VERSION 5.7 ;
  NOWIREEXTENSIONATPIN ON ;
  DIVIDERCHAR "/" ;
  BUSBITCHARS "[]" ;
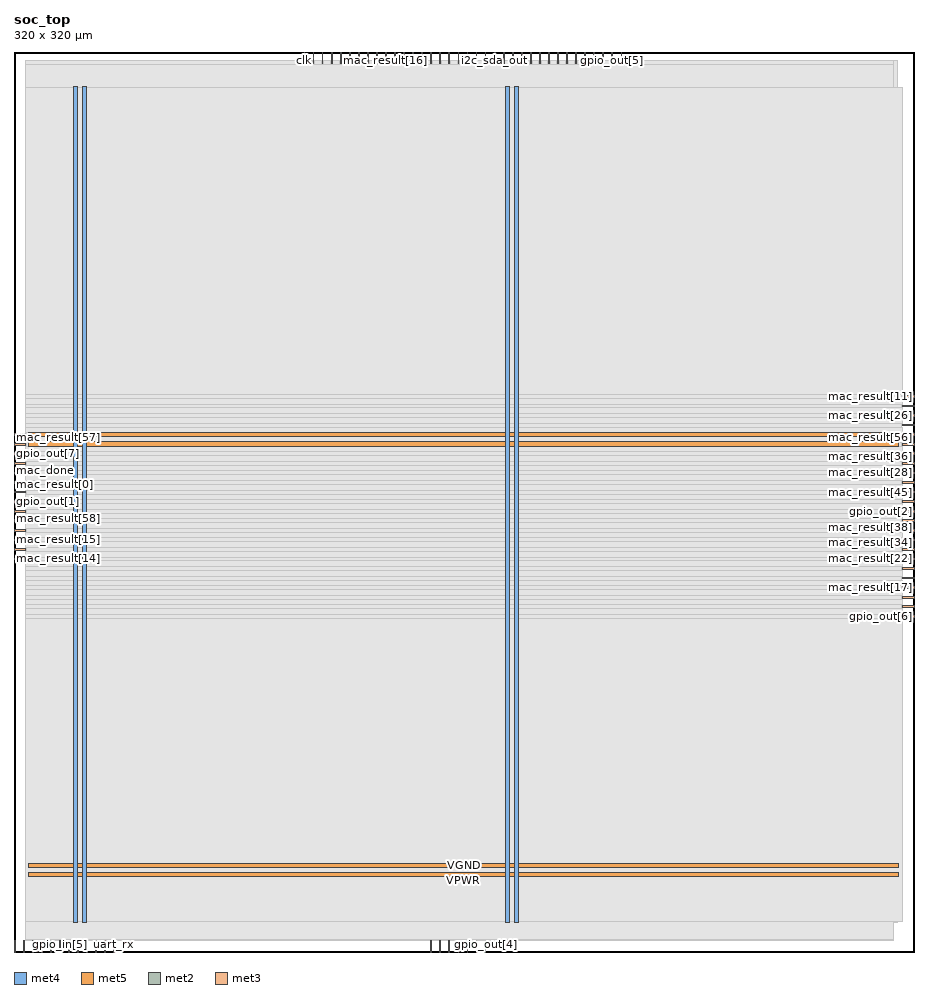
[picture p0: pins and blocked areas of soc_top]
MACRO soc_top
  CLASS BLOCK ;
  FOREIGN soc_top ;
  ORIGIN 0.000 0.000 ;
  SIZE 320.000 BY 320.000 ;
  PIN VGND
    DIRECTION INOUT ;
    USE GROUND ;
    PORT
      LAYER met4 ;
        RECT 24.340 10.640 25.940 307.600 ;
    END
    PORT
      LAYER met4 ;
        RECT 177.940 10.640 179.540 307.600 ;
    END
    PORT
      LAYER met5 ;
        RECT 5.280 30.030 314.420 31.630 ;
    END
    PORT
      LAYER met5 ;
        RECT 5.280 183.210 314.420 184.810 ;
    END
  END VGND
  PIN VPWR
    DIRECTION INOUT ;
    USE POWER ;
    PORT
      LAYER met4 ;
        RECT 21.040 10.640 22.640 307.600 ;
    END
    PORT
      LAYER met4 ;
        RECT 174.640 10.640 176.240 307.600 ;
    END
    PORT
      LAYER met5 ;
        RECT 5.280 26.730 314.420 28.330 ;
    END
    PORT
      LAYER met5 ;
        RECT 5.280 179.910 314.420 181.510 ;
    END
  END VPWR
  PIN clk
    DIRECTION INPUT ;
    USE SIGNAL ;
    ANTENNAGATEAREA 0.852000 ;
    PORT
      LAYER met2 ;
        RECT 103.130 316.000 103.410 320.000 ;
    END
  END clk
  PIN gpio_in[0]
    DIRECTION INPUT ;
    USE SIGNAL ;
    PORT
      LAYER met2 ;
        RECT 0.090 0.000 0.370 4.000 ;
    END
  END gpio_in[0]
  PIN gpio_in[1]
    DIRECTION INPUT ;
    USE SIGNAL ;
    PORT
      LAYER met2 ;
        RECT 3.310 0.000 3.590 4.000 ;
    END
  END gpio_in[1]
  PIN gpio_in[2]
    DIRECTION INPUT ;
    USE SIGNAL ;
    PORT
      LAYER met2 ;
        RECT 6.530 0.000 6.810 4.000 ;
    END
  END gpio_in[2]
  PIN gpio_in[3]
    DIRECTION INPUT ;
    USE SIGNAL ;
    PORT
      LAYER met2 ;
        RECT 9.750 0.000 10.030 4.000 ;
    END
  END gpio_in[3]
  PIN gpio_in[4]
    DIRECTION INPUT ;
    USE SIGNAL ;
    PORT
      LAYER met2 ;
        RECT 12.970 0.000 13.250 4.000 ;
    END
  END gpio_in[4]
  PIN gpio_in[5]
    DIRECTION INPUT ;
    USE SIGNAL ;
    PORT
      LAYER met2 ;
        RECT 16.190 0.000 16.470 4.000 ;
    END
  END gpio_in[5]
  PIN gpio_in[6]
    DIRECTION INPUT ;
    USE SIGNAL ;
    PORT
      LAYER met2 ;
        RECT 19.410 0.000 19.690 4.000 ;
    END
  END gpio_in[6]
  PIN gpio_in[7]
    DIRECTION INPUT ;
    USE SIGNAL ;
    PORT
      LAYER met2 ;
        RECT 22.630 0.000 22.910 4.000 ;
    END
  END gpio_in[7]
  PIN gpio_out[0]
    DIRECTION OUTPUT ;
    USE SIGNAL ;
    PORT
      LAYER met3 ;
        RECT 0.000 183.640 4.000 184.240 ;
    END
  END gpio_out[0]
  PIN gpio_out[1]
    DIRECTION OUTPUT ;
    USE SIGNAL ;
    PORT
      LAYER met3 ;
        RECT 0.000 159.840 4.000 160.440 ;
    END
  END gpio_out[1]
  PIN gpio_out[2]
    DIRECTION OUTPUT ;
    USE SIGNAL ;
    PORT
      LAYER met3 ;
        RECT 316.000 156.440 320.000 157.040 ;
    END
  END gpio_out[2]
  PIN gpio_out[3]
    DIRECTION OUTPUT ;
    USE SIGNAL ;
    PORT
      LAYER met2 ;
        RECT 112.790 316.000 113.070 320.000 ;
    END
  END gpio_out[3]
  PIN gpio_out[4]
    DIRECTION OUTPUT ;
    USE SIGNAL ;
    PORT
      LAYER met2 ;
        RECT 167.530 0.000 167.810 4.000 ;
    END
  END gpio_out[4]
  PIN gpio_out[5]
    DIRECTION OUTPUT ;
    USE SIGNAL ;
    PORT
      LAYER met2 ;
        RECT 212.610 316.000 212.890 320.000 ;
    END
  END gpio_out[5]
  PIN gpio_out[6]
    DIRECTION OUTPUT ;
    USE SIGNAL ;
    PORT
      LAYER met3 ;
        RECT 316.000 119.040 320.000 119.640 ;
    END
  END gpio_out[6]
  PIN gpio_out[7]
    DIRECTION OUTPUT ;
    USE SIGNAL ;
    PORT
      LAYER met3 ;
        RECT 0.000 176.840 4.000 177.440 ;
    END
  END gpio_out[7]
  PIN i2c_scl
    DIRECTION OUTPUT ;
    USE SIGNAL ;
    ANTENNADIFFAREA 0.340600 ;
    PORT
      LAYER met2 ;
        RECT 151.430 316.000 151.710 320.000 ;
    END
  END i2c_scl
  PIN i2c_sda_in
    DIRECTION INPUT ;
    USE SIGNAL ;
    PORT
      LAYER met2 ;
        RECT 25.850 0.000 26.130 4.000 ;
    END
  END i2c_sda_in
  PIN i2c_sda_out
    DIRECTION OUTPUT ;
    USE SIGNAL ;
    PORT
      LAYER met2 ;
        RECT 170.750 316.000 171.030 320.000 ;
    END
  END i2c_sda_out
  PIN mac_done
    DIRECTION OUTPUT ;
    USE SIGNAL ;
    PORT
      LAYER met3 ;
        RECT 0.000 173.440 4.000 174.040 ;
    END
  END mac_done
  PIN mac_result[0]
    DIRECTION OUTPUT ;
    USE SIGNAL ;
    PORT
      LAYER met3 ;
        RECT 0.000 163.240 4.000 163.840 ;
    END
  END mac_result[0]
  PIN mac_result[10]
    DIRECTION OUTPUT ;
    USE SIGNAL ;
    PORT
      LAYER met3 ;
        RECT 316.000 122.440 320.000 123.040 ;
    END
  END mac_result[10]
  PIN mac_result[11]
    DIRECTION OUTPUT ;
    USE SIGNAL ;
    PORT
      LAYER met3 ;
        RECT 316.000 197.240 320.000 197.840 ;
    END
  END mac_result[11]
  PIN mac_result[12]
    DIRECTION OUTPUT ;
    USE SIGNAL ;
    PORT
      LAYER met2 ;
        RECT 177.190 316.000 177.470 320.000 ;
    END
  END mac_result[12]
  PIN mac_result[13]
    DIRECTION OUTPUT ;
    USE SIGNAL ;
    PORT
      LAYER met3 ;
        RECT 316.000 166.640 320.000 167.240 ;
    END
  END mac_result[13]
  PIN mac_result[14]
    DIRECTION OUTPUT ;
    USE SIGNAL ;
    PORT
      LAYER met3 ;
        RECT 0.000 139.440 4.000 140.040 ;
    END
  END mac_result[14]
  PIN mac_result[15]
    DIRECTION OUTPUT ;
    USE SIGNAL ;
    PORT
      LAYER met3 ;
        RECT 0.000 146.240 4.000 146.840 ;
    END
  END mac_result[15]
  PIN mac_result[16]
    DIRECTION OUTPUT ;
    USE SIGNAL ;
    PORT
      LAYER met2 ;
        RECT 132.110 316.000 132.390 320.000 ;
    END
  END mac_result[16]
  PIN mac_result[17]
    DIRECTION OUTPUT ;
    USE SIGNAL ;
    PORT
      LAYER met3 ;
        RECT 316.000 129.240 320.000 129.840 ;
    END
  END mac_result[17]
  PIN mac_result[18]
    DIRECTION OUTPUT ;
    USE SIGNAL ;
    PORT
      LAYER met3 ;
        RECT 0.000 166.640 4.000 167.240 ;
    END
  END mac_result[18]
  PIN mac_result[19]
    DIRECTION OUTPUT ;
    USE SIGNAL ;
    PORT
      LAYER met2 ;
        RECT 164.310 316.000 164.590 320.000 ;
    END
  END mac_result[19]
  PIN mac_result[1]
    DIRECTION OUTPUT ;
    USE SIGNAL ;
    PORT
      LAYER met2 ;
        RECT 154.650 316.000 154.930 320.000 ;
    END
  END mac_result[1]
  PIN mac_result[20]
    DIRECTION OUTPUT ;
    USE SIGNAL ;
    PORT
      LAYER met2 ;
        RECT 122.450 316.000 122.730 320.000 ;
    END
  END mac_result[20]
  PIN mac_result[21]
    DIRECTION OUTPUT ;
    USE SIGNAL ;
    PORT
      LAYER met3 ;
        RECT 0.000 170.040 4.000 170.640 ;
    END
  END mac_result[21]
  PIN mac_result[22]
    DIRECTION OUTPUT ;
    USE SIGNAL ;
    PORT
      LAYER met3 ;
        RECT 316.000 139.440 320.000 140.040 ;
    END
  END mac_result[22]
  PIN mac_result[23]
    DIRECTION OUTPUT ;
    USE SIGNAL ;
    PORT
      LAYER met2 ;
        RECT 125.670 316.000 125.950 320.000 ;
    END
  END mac_result[23]
  PIN mac_result[24]
    DIRECTION OUTPUT ;
    USE SIGNAL ;
    PORT
      LAYER met2 ;
        RECT 167.530 316.000 167.810 320.000 ;
    END
  END mac_result[24]
  PIN mac_result[25]
    DIRECTION OUTPUT ;
    USE SIGNAL ;
    PORT
      LAYER met2 ;
        RECT 190.070 316.000 190.350 320.000 ;
    END
  END mac_result[25]
  PIN mac_result[26]
    DIRECTION OUTPUT ;
    USE SIGNAL ;
    PORT
      LAYER met3 ;
        RECT 316.000 190.440 320.000 191.040 ;
    END
  END mac_result[26]
  PIN mac_result[27]
    DIRECTION OUTPUT ;
    USE SIGNAL ;
    PORT
      LAYER met2 ;
        RECT 202.950 316.000 203.230 320.000 ;
    END
  END mac_result[27]
  PIN mac_result[28]
    DIRECTION OUTPUT ;
    USE SIGNAL ;
    PORT
      LAYER met3 ;
        RECT 316.000 170.040 320.000 170.640 ;
    END
  END mac_result[28]
  PIN mac_result[29]
    DIRECTION OUTPUT ;
    USE SIGNAL ;
    PORT
      LAYER met2 ;
        RECT 128.890 316.000 129.170 320.000 ;
    END
  END mac_result[29]
  PIN mac_result[2]
    DIRECTION OUTPUT ;
    USE SIGNAL ;
    PORT
      LAYER met2 ;
        RECT 161.090 316.000 161.370 320.000 ;
    END
  END mac_result[2]
  PIN mac_result[30]
    DIRECTION OUTPUT ;
    USE SIGNAL ;
    PORT
      LAYER met2 ;
        RECT 116.010 316.000 116.290 320.000 ;
    END
  END mac_result[30]
  PIN mac_result[31]
    DIRECTION OUTPUT ;
    USE SIGNAL ;
    PORT
      LAYER met3 ;
        RECT 316.000 136.040 320.000 136.640 ;
    END
  END mac_result[31]
  PIN mac_result[32]
    DIRECTION OUTPUT ;
    USE SIGNAL ;
    PORT
      LAYER met2 ;
        RECT 161.090 0.000 161.370 4.000 ;
    END
  END mac_result[32]
  PIN mac_result[33]
    DIRECTION OUTPUT ;
    USE SIGNAL ;
    PORT
      LAYER met2 ;
        RECT 138.550 316.000 138.830 320.000 ;
    END
  END mac_result[33]
  PIN mac_result[34]
    DIRECTION OUTPUT ;
    USE SIGNAL ;
    PORT
      LAYER met3 ;
        RECT 316.000 142.840 320.000 143.440 ;
    END
  END mac_result[34]
  PIN mac_result[35]
    DIRECTION OUTPUT ;
    USE SIGNAL ;
    PORT
      LAYER met2 ;
        RECT 148.210 0.000 148.490 4.000 ;
    END
  END mac_result[35]
  PIN mac_result[36]
    DIRECTION OUTPUT ;
    USE SIGNAL ;
    PORT
      LAYER met3 ;
        RECT 316.000 173.440 320.000 174.040 ;
    END
  END mac_result[36]
  PIN mac_result[37]
    DIRECTION OUTPUT ;
    USE SIGNAL ;
    PORT
      LAYER met2 ;
        RECT 196.510 316.000 196.790 320.000 ;
    END
  END mac_result[37]
  PIN mac_result[38]
    DIRECTION OUTPUT ;
    USE SIGNAL ;
    PORT
      LAYER met3 ;
        RECT 316.000 153.040 320.000 153.640 ;
    END
  END mac_result[38]
  PIN mac_result[39]
    DIRECTION OUTPUT ;
    USE SIGNAL ;
    PORT
      LAYER met3 ;
        RECT 316.000 183.640 320.000 184.240 ;
    END
  END mac_result[39]
  PIN mac_result[3]
    DIRECTION OUTPUT ;
    USE SIGNAL ;
    PORT
      LAYER met2 ;
        RECT 215.830 316.000 216.110 320.000 ;
    END
  END mac_result[3]
  PIN mac_result[40]
    DIRECTION OUTPUT ;
    USE SIGNAL ;
    PORT
      LAYER met2 ;
        RECT 180.410 316.000 180.690 320.000 ;
    END
  END mac_result[40]
  PIN mac_result[41]
    DIRECTION OUTPUT ;
    USE SIGNAL ;
    PORT
      LAYER met2 ;
        RECT 193.290 316.000 193.570 320.000 ;
    END
  END mac_result[41]
  PIN mac_result[42]
    DIRECTION OUTPUT ;
    USE SIGNAL ;
    PORT
      LAYER met2 ;
        RECT 209.390 316.000 209.670 320.000 ;
    END
  END mac_result[42]
  PIN mac_result[43]
    DIRECTION OUTPUT ;
    USE SIGNAL ;
    PORT
      LAYER met3 ;
        RECT 316.000 132.640 320.000 133.240 ;
    END
  END mac_result[43]
  PIN mac_result[44]
    DIRECTION OUTPUT ;
    USE SIGNAL ;
    PORT
      LAYER met3 ;
        RECT 316.000 176.840 320.000 177.440 ;
    END
  END mac_result[44]
  PIN mac_result[45]
    DIRECTION OUTPUT ;
    USE SIGNAL ;
    PORT
      LAYER met3 ;
        RECT 316.000 163.240 320.000 163.840 ;
    END
  END mac_result[45]
  PIN mac_result[46]
    DIRECTION OUTPUT ;
    USE SIGNAL ;
    PORT
      LAYER met3 ;
        RECT 0.000 149.640 4.000 150.240 ;
    END
  END mac_result[46]
  PIN mac_result[47]
    DIRECTION OUTPUT ;
    USE SIGNAL ;
    PORT
      LAYER met2 ;
        RECT 206.170 316.000 206.450 320.000 ;
    END
  END mac_result[47]
  PIN mac_result[48]
    DIRECTION OUTPUT ;
    USE SIGNAL ;
    PORT
      LAYER met2 ;
        RECT 119.230 316.000 119.510 320.000 ;
    END
  END mac_result[48]
  PIN mac_result[49]
    DIRECTION OUTPUT ;
    USE SIGNAL ;
    PORT
      LAYER met2 ;
        RECT 157.870 0.000 158.150 4.000 ;
    END
  END mac_result[49]
  PIN mac_result[4]
    DIRECTION OUTPUT ;
    USE SIGNAL ;
    PORT
      LAYER met2 ;
        RECT 135.330 316.000 135.610 320.000 ;
    END
  END mac_result[4]
  PIN mac_result[50]
    DIRECTION OUTPUT ;
    USE SIGNAL ;
    PORT
      LAYER met2 ;
        RECT 144.990 316.000 145.270 320.000 ;
    END
  END mac_result[50]
  PIN mac_result[51]
    DIRECTION OUTPUT ;
    USE SIGNAL ;
    PORT
      LAYER met2 ;
        RECT 151.430 0.000 151.710 4.000 ;
    END
  END mac_result[51]
  PIN mac_result[52]
    DIRECTION OUTPUT ;
    USE SIGNAL ;
    PORT
      LAYER met2 ;
        RECT 154.650 0.000 154.930 4.000 ;
    END
  END mac_result[52]
  PIN mac_result[53]
    DIRECTION OUTPUT ;
    USE SIGNAL ;
    PORT
      LAYER met3 ;
        RECT 316.000 149.640 320.000 150.240 ;
    END
  END mac_result[53]
  PIN mac_result[54]
    DIRECTION OUTPUT ;
    USE SIGNAL ;
    PORT
      LAYER met2 ;
        RECT 109.570 316.000 109.850 320.000 ;
    END
  END mac_result[54]
  PIN mac_result[55]
    DIRECTION OUTPUT ;
    USE SIGNAL ;
    PORT
      LAYER met3 ;
        RECT 316.000 125.840 320.000 126.440 ;
    END
  END mac_result[55]
  PIN mac_result[56]
    DIRECTION OUTPUT ;
    USE SIGNAL ;
    PORT
      LAYER met3 ;
        RECT 316.000 180.240 320.000 180.840 ;
    END
  END mac_result[56]
  PIN mac_result[57]
    DIRECTION OUTPUT ;
    USE SIGNAL ;
    PORT
      LAYER met3 ;
        RECT 0.000 180.240 4.000 180.840 ;
    END
  END mac_result[57]
  PIN mac_result[58]
    DIRECTION OUTPUT ;
    USE SIGNAL ;
    PORT
      LAYER met3 ;
        RECT 0.000 156.440 4.000 157.040 ;
    END
  END mac_result[58]
  PIN mac_result[59]
    DIRECTION OUTPUT ;
    USE SIGNAL ;
    PORT
      LAYER met2 ;
        RECT 199.730 316.000 200.010 320.000 ;
    END
  END mac_result[59]
  PIN mac_result[5]
    DIRECTION OUTPUT ;
    USE SIGNAL ;
    PORT
      LAYER met3 ;
        RECT 316.000 187.040 320.000 187.640 ;
    END
  END mac_result[5]
  PIN mac_result[60]
    DIRECTION OUTPUT ;
    USE SIGNAL ;
    PORT
      LAYER met2 ;
        RECT 186.850 316.000 187.130 320.000 ;
    END
  END mac_result[60]
  PIN mac_result[61]
    DIRECTION OUTPUT ;
    USE SIGNAL ;
    PORT
      LAYER met2 ;
        RECT 148.210 316.000 148.490 320.000 ;
    END
  END mac_result[61]
  PIN mac_result[62]
    DIRECTION OUTPUT ;
    USE SIGNAL ;
    PORT
      LAYER met3 ;
        RECT 316.000 146.240 320.000 146.840 ;
    END
  END mac_result[62]
  PIN mac_result[63]
    DIRECTION OUTPUT ;
    USE SIGNAL ;
    PORT
      LAYER met3 ;
        RECT 316.000 193.840 320.000 194.440 ;
    END
  END mac_result[63]
  PIN mac_result[6]
    DIRECTION OUTPUT ;
    USE SIGNAL ;
    PORT
      LAYER met3 ;
        RECT 316.000 159.840 320.000 160.440 ;
    END
  END mac_result[6]
  PIN mac_result[7]
    DIRECTION OUTPUT ;
    USE SIGNAL ;
    PORT
      LAYER met2 ;
        RECT 183.630 316.000 183.910 320.000 ;
    END
  END mac_result[7]
  PIN mac_result[8]
    DIRECTION OUTPUT ;
    USE SIGNAL ;
    PORT
      LAYER met2 ;
        RECT 173.970 316.000 174.250 320.000 ;
    END
  END mac_result[8]
  PIN mac_result[9]
    DIRECTION OUTPUT ;
    USE SIGNAL ;
    PORT
      LAYER met2 ;
        RECT 141.770 316.000 142.050 320.000 ;
    END
  END mac_result[9]
  PIN rst
    DIRECTION INPUT ;
    USE SIGNAL ;
    PORT
      LAYER met2 ;
        RECT 29.070 0.000 29.350 4.000 ;
    END
  END rst
  PIN spi_cs
    DIRECTION OUTPUT ;
    USE SIGNAL ;
    PORT
      LAYER met3 ;
        RECT 0.000 153.040 4.000 153.640 ;
    END
  END spi_cs
  PIN spi_miso
    DIRECTION INPUT ;
    USE SIGNAL ;
    PORT
      LAYER met2 ;
        RECT 32.290 0.000 32.570 4.000 ;
    END
  END spi_miso
  PIN spi_mosi
    DIRECTION OUTPUT ;
    USE SIGNAL ;
    PORT
      LAYER met2 ;
        RECT 164.310 0.000 164.590 4.000 ;
    END
  END spi_mosi
  PIN spi_sclk
    DIRECTION OUTPUT ;
    USE SIGNAL ;
    ANTENNADIFFAREA 0.340600 ;
    PORT
      LAYER met2 ;
        RECT 157.870 316.000 158.150 320.000 ;
    END
  END spi_sclk
  PIN timer_irq
    DIRECTION OUTPUT ;
    USE SIGNAL ;
    PORT
      LAYER met2 ;
        RECT 106.350 316.000 106.630 320.000 ;
    END
  END timer_irq
  PIN uart_rx
    DIRECTION INPUT ;
    USE SIGNAL ;
    PORT
      LAYER met2 ;
        RECT 35.510 0.000 35.790 4.000 ;
    END
  END uart_rx
  PIN uart_tx
    DIRECTION OUTPUT ;
    USE SIGNAL ;
    PORT
      LAYER met3 ;
        RECT 0.000 142.840 4.000 143.440 ;
    END
  END uart_tx
  OBS
      LAYER nwell ;
        RECT 5.330 10.795 314.370 307.550 ;
      LAYER li1 ;
        RECT 5.520 10.795 314.180 307.445 ;
      LAYER met1 ;
        RECT 4.210 10.640 314.180 316.840 ;
      LAYER met2 ;
        RECT 4.230 315.720 102.850 316.870 ;
        RECT 103.690 315.720 106.070 316.870 ;
        RECT 106.910 315.720 109.290 316.870 ;
        RECT 110.130 315.720 112.510 316.870 ;
        RECT 113.350 315.720 115.730 316.870 ;
        RECT 116.570 315.720 118.950 316.870 ;
        RECT 119.790 315.720 122.170 316.870 ;
        RECT 123.010 315.720 125.390 316.870 ;
        RECT 126.230 315.720 128.610 316.870 ;
        RECT 129.450 315.720 131.830 316.870 ;
        RECT 132.670 315.720 135.050 316.870 ;
        RECT 135.890 315.720 138.270 316.870 ;
        RECT 139.110 315.720 141.490 316.870 ;
        RECT 142.330 315.720 144.710 316.870 ;
        RECT 145.550 315.720 147.930 316.870 ;
        RECT 148.770 315.720 151.150 316.870 ;
        RECT 151.990 315.720 154.370 316.870 ;
        RECT 155.210 315.720 157.590 316.870 ;
        RECT 158.430 315.720 160.810 316.870 ;
        RECT 161.650 315.720 164.030 316.870 ;
        RECT 164.870 315.720 167.250 316.870 ;
        RECT 168.090 315.720 170.470 316.870 ;
        RECT 171.310 315.720 173.690 316.870 ;
        RECT 174.530 315.720 176.910 316.870 ;
        RECT 177.750 315.720 180.130 316.870 ;
        RECT 180.970 315.720 183.350 316.870 ;
        RECT 184.190 315.720 186.570 316.870 ;
        RECT 187.410 315.720 189.790 316.870 ;
        RECT 190.630 315.720 193.010 316.870 ;
        RECT 193.850 315.720 196.230 316.870 ;
        RECT 197.070 315.720 199.450 316.870 ;
        RECT 200.290 315.720 202.670 316.870 ;
        RECT 203.510 315.720 205.890 316.870 ;
        RECT 206.730 315.720 209.110 316.870 ;
        RECT 209.950 315.720 212.330 316.870 ;
        RECT 213.170 315.720 215.550 316.870 ;
        RECT 216.390 315.720 312.710 316.870 ;
        RECT 4.230 4.280 312.710 315.720 ;
        RECT 4.230 4.000 6.250 4.280 ;
        RECT 7.090 4.000 9.470 4.280 ;
        RECT 10.310 4.000 12.690 4.280 ;
        RECT 13.530 4.000 15.910 4.280 ;
        RECT 16.750 4.000 19.130 4.280 ;
        RECT 19.970 4.000 22.350 4.280 ;
        RECT 23.190 4.000 25.570 4.280 ;
        RECT 26.410 4.000 28.790 4.280 ;
        RECT 29.630 4.000 32.010 4.280 ;
        RECT 32.850 4.000 35.230 4.280 ;
        RECT 36.070 4.000 147.930 4.280 ;
        RECT 148.770 4.000 151.150 4.280 ;
        RECT 151.990 4.000 154.370 4.280 ;
        RECT 155.210 4.000 157.590 4.280 ;
        RECT 158.430 4.000 160.810 4.280 ;
        RECT 161.650 4.000 164.030 4.280 ;
        RECT 164.870 4.000 167.250 4.280 ;
        RECT 168.090 4.000 312.710 4.280 ;
      LAYER met3 ;
        RECT 3.990 198.240 316.000 307.525 ;
        RECT 3.990 196.840 315.600 198.240 ;
        RECT 3.990 194.840 316.000 196.840 ;
        RECT 3.990 193.440 315.600 194.840 ;
        RECT 3.990 191.440 316.000 193.440 ;
        RECT 3.990 190.040 315.600 191.440 ;
        RECT 3.990 188.040 316.000 190.040 ;
        RECT 3.990 186.640 315.600 188.040 ;
        RECT 3.990 184.640 316.000 186.640 ;
        RECT 4.400 183.240 315.600 184.640 ;
        RECT 3.990 181.240 316.000 183.240 ;
        RECT 4.400 179.840 315.600 181.240 ;
        RECT 3.990 177.840 316.000 179.840 ;
        RECT 4.400 176.440 315.600 177.840 ;
        RECT 3.990 174.440 316.000 176.440 ;
        RECT 4.400 173.040 315.600 174.440 ;
        RECT 3.990 171.040 316.000 173.040 ;
        RECT 4.400 169.640 315.600 171.040 ;
        RECT 3.990 167.640 316.000 169.640 ;
        RECT 4.400 166.240 315.600 167.640 ;
        RECT 3.990 164.240 316.000 166.240 ;
        RECT 4.400 162.840 315.600 164.240 ;
        RECT 3.990 160.840 316.000 162.840 ;
        RECT 4.400 159.440 315.600 160.840 ;
        RECT 3.990 157.440 316.000 159.440 ;
        RECT 4.400 156.040 315.600 157.440 ;
        RECT 3.990 154.040 316.000 156.040 ;
        RECT 4.400 152.640 315.600 154.040 ;
        RECT 3.990 150.640 316.000 152.640 ;
        RECT 4.400 149.240 315.600 150.640 ;
        RECT 3.990 147.240 316.000 149.240 ;
        RECT 4.400 145.840 315.600 147.240 ;
        RECT 3.990 143.840 316.000 145.840 ;
        RECT 4.400 142.440 315.600 143.840 ;
        RECT 3.990 140.440 316.000 142.440 ;
        RECT 4.400 139.040 315.600 140.440 ;
        RECT 3.990 137.040 316.000 139.040 ;
        RECT 3.990 135.640 315.600 137.040 ;
        RECT 3.990 133.640 316.000 135.640 ;
        RECT 3.990 132.240 315.600 133.640 ;
        RECT 3.990 130.240 316.000 132.240 ;
        RECT 3.990 128.840 315.600 130.240 ;
        RECT 3.990 126.840 316.000 128.840 ;
        RECT 3.990 125.440 315.600 126.840 ;
        RECT 3.990 123.440 316.000 125.440 ;
        RECT 3.990 122.040 315.600 123.440 ;
        RECT 3.990 120.040 316.000 122.040 ;
        RECT 3.990 118.640 315.600 120.040 ;
        RECT 3.990 10.715 316.000 118.640 ;
  END
END soc_top
END LIBRARY

